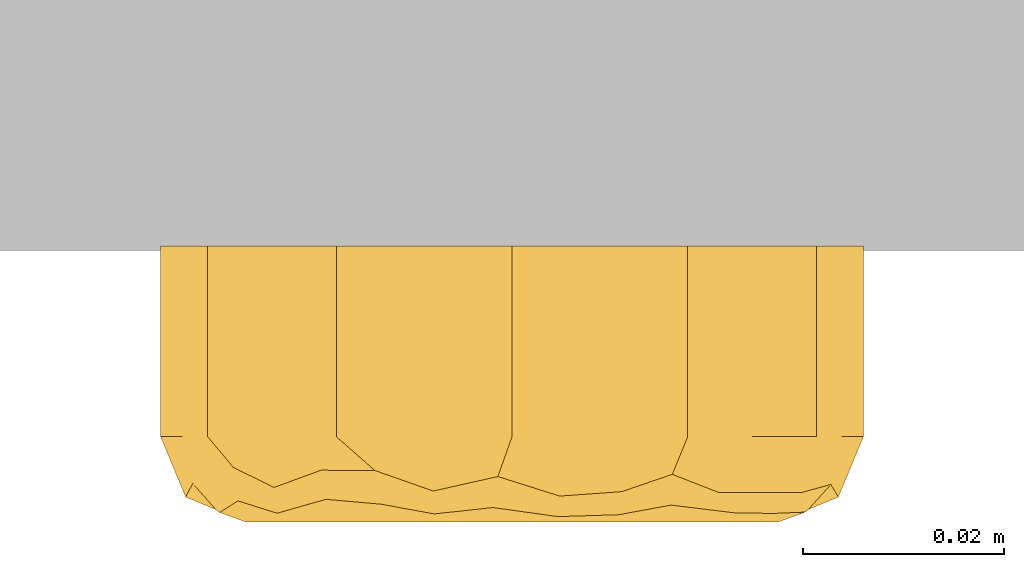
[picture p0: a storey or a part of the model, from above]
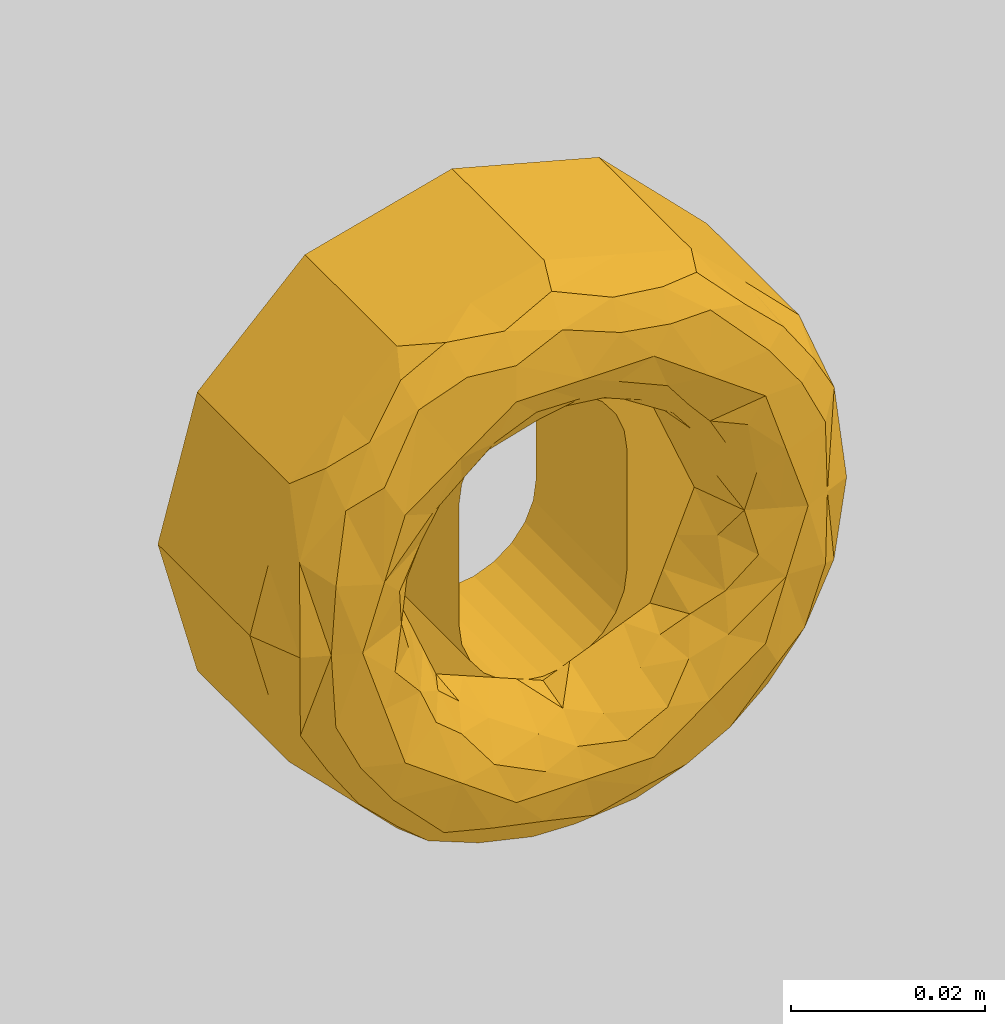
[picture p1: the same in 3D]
Properties of the parts of a building model (IFC2X3)

# File
Description: ViewDefinition [CoordinationView_V2.0]
File name: Project Number
Time: 2019-11-04T23:18:00
Written by: The EXPRESS Data Manager Version 5.02.0100.07 : 28 Aug 2013
Made in: 20190731_1515(x64) - Exporter 20.1.1.1 - Alternate UI 20.1.1.1
Comment: STEP Physical File produced by: The EXPRESS Data Manager Version 5.02.0100.07 : 28 Aug 2013 * Module: EDMstepFileFactory/EDMstandAlone * Creation date: Mon Nov 04 23:18:00 2019 * Host: LT-GBA1 * Database: C:\Users\gba\AppData\Local\Temp\4ebb9ef7-f56d-4641-bac5-bb568615496d\ca3bb4ab-242d-4979-8952-f961001cd77e\ifc * Database version: 5507 * Database creation date: Mon Nov 04 23:18:00 2019 * Schema: IFC2X3 * Model: DataRepository.ifc * Model creation date: Mon Nov 04 23:18:00 2019 * Header model: DataRepository.ifc_HeaderModel * Header model creation date: Mon Nov 04 23:18:00 2019 * EDMuser: sdai-user * EDMgroup: sdai-group * License ID and type: 5605 : Permanent license. Expiry date: * EDMstepFileFactory options: 020000

# IfcProject, Project Number
LongName: Project Name; Phase: Project Status

# IfcSite, Default
RefLatitude: 42, 21, 31, 181945; RefLongitude: -71, -3, -24, -263305; RefElevation: 0 ft

# IfcBuilding
Pset_BuildingCommon - NumberOfStoreys: 1
Pset_ProductRequirements - Category: Project Information

# IfcBuildingStorey: Level:1/4" Head, Level 1
LongName: Level 1; Elevation: 0 ft
Pset_AirSideSystemInformation - Name: Level 1
Pset_ProductRequirements - Name: Level 1; Category: Levels

# IfcDoor: 36" x 84", Single-Flush:36" x 84":339204
In: Level 1
Type - OperationType: SINGLE_SWING_RIGHT; ParameterTakesPrecedence: no; Sizeable: no; Classification: C1020 Interior Doors (Uniformat); Material: Door - Frame, Door - Panel
Type - Single-Flush:36" x 84":339204 - PanelOperation: SWINGING
OverallHeight: 7 ft; OverallWidth: 3 ft
Pset_DoorCommon - IsExternal: no; Reference: 36" x 84"
Pset_ProductRequirements - Category: Doors
Pset_QuantityTakeOff - Reference: 36" x 84"

# IfcDoor: dline_Hardware_TomDixonCollection_Escutcheons_Oval_Half_SnapOn_18.25, 12.9002.02.210:dline_Hardware_TomDixonCollection_Escutcheons_Oval_Half_SnapOn_18.25:340307
In: Level 1
Type - OperationType: DOUBLE_SWING_RIGHT; ParameterTakesPrecedence: no; Sizeable: no
Type - 12.9002.02.210:dline_Hardware_TomDixonCollection_Escutcheons_Oval_Half_SnapOn_18.25:340307 - PanelOperation: DOUBLE_ACTING
OverallHeight: 0.451914 ft; OverallWidth: 0.442913 ft
Pset_ConcreteElementGeneral - FireRating: n/a
Pset_DoorCommon - IsExternal: no; Reference: n/a; FireRating: n/a; AcousticRating: n/a; SecurityRating: n/a; GlazingAreaFraction: 0; HandicapAccessible: no; FireExit: no; SelfClosing: no; SmokeStop: no
Pset_ElementShading - Color: Steel
Pset_ManufacturerOccurrence - BarCode: n/a; SerialNumber: n/a
Pset_ManufacturerTypeInformation - ModelReference: 45-25-60/315; Manufacturer: info@dline.com
Pset_PrecastConcreteElementGeneral - SerialNumber: n/a
Pset_ProductRequirements - Name: dline_Hardware_TomDixonCollection_Escutcheons_Oval_Half_SnapOn_18.25; Category: Doors
Pset_QuantityTakeOff - Reference: n/a

# IfcWallStandardCase: Basic Wall:Generic - 8", Basic Wall:Generic - 8":339176
In: Level 1
Type - PredefinedType: STANDARD; Material: Default Wall 0.666667 ft
Type - Pset_ElementShading - Roughness: 1 ft
Type - Pset_ProductRequirements - Category: Walls
Type - Pset_QuantityTakeOff - Reference: Generic - 8"
Type - Pset_ReinforcementBarPitchOfWall - Reference: Generic - 8"
Type - Pset_WallCommon - Reference: Generic - 8"; IsExternal: no
Classification: B2010 Exterior Walls (Uniformat)
Pset_QuantityTakeOff - sets with these values: 2
Pset_WallCommon - IsExternal: yes; ExtendToStructure: no; LoadBearing: no
